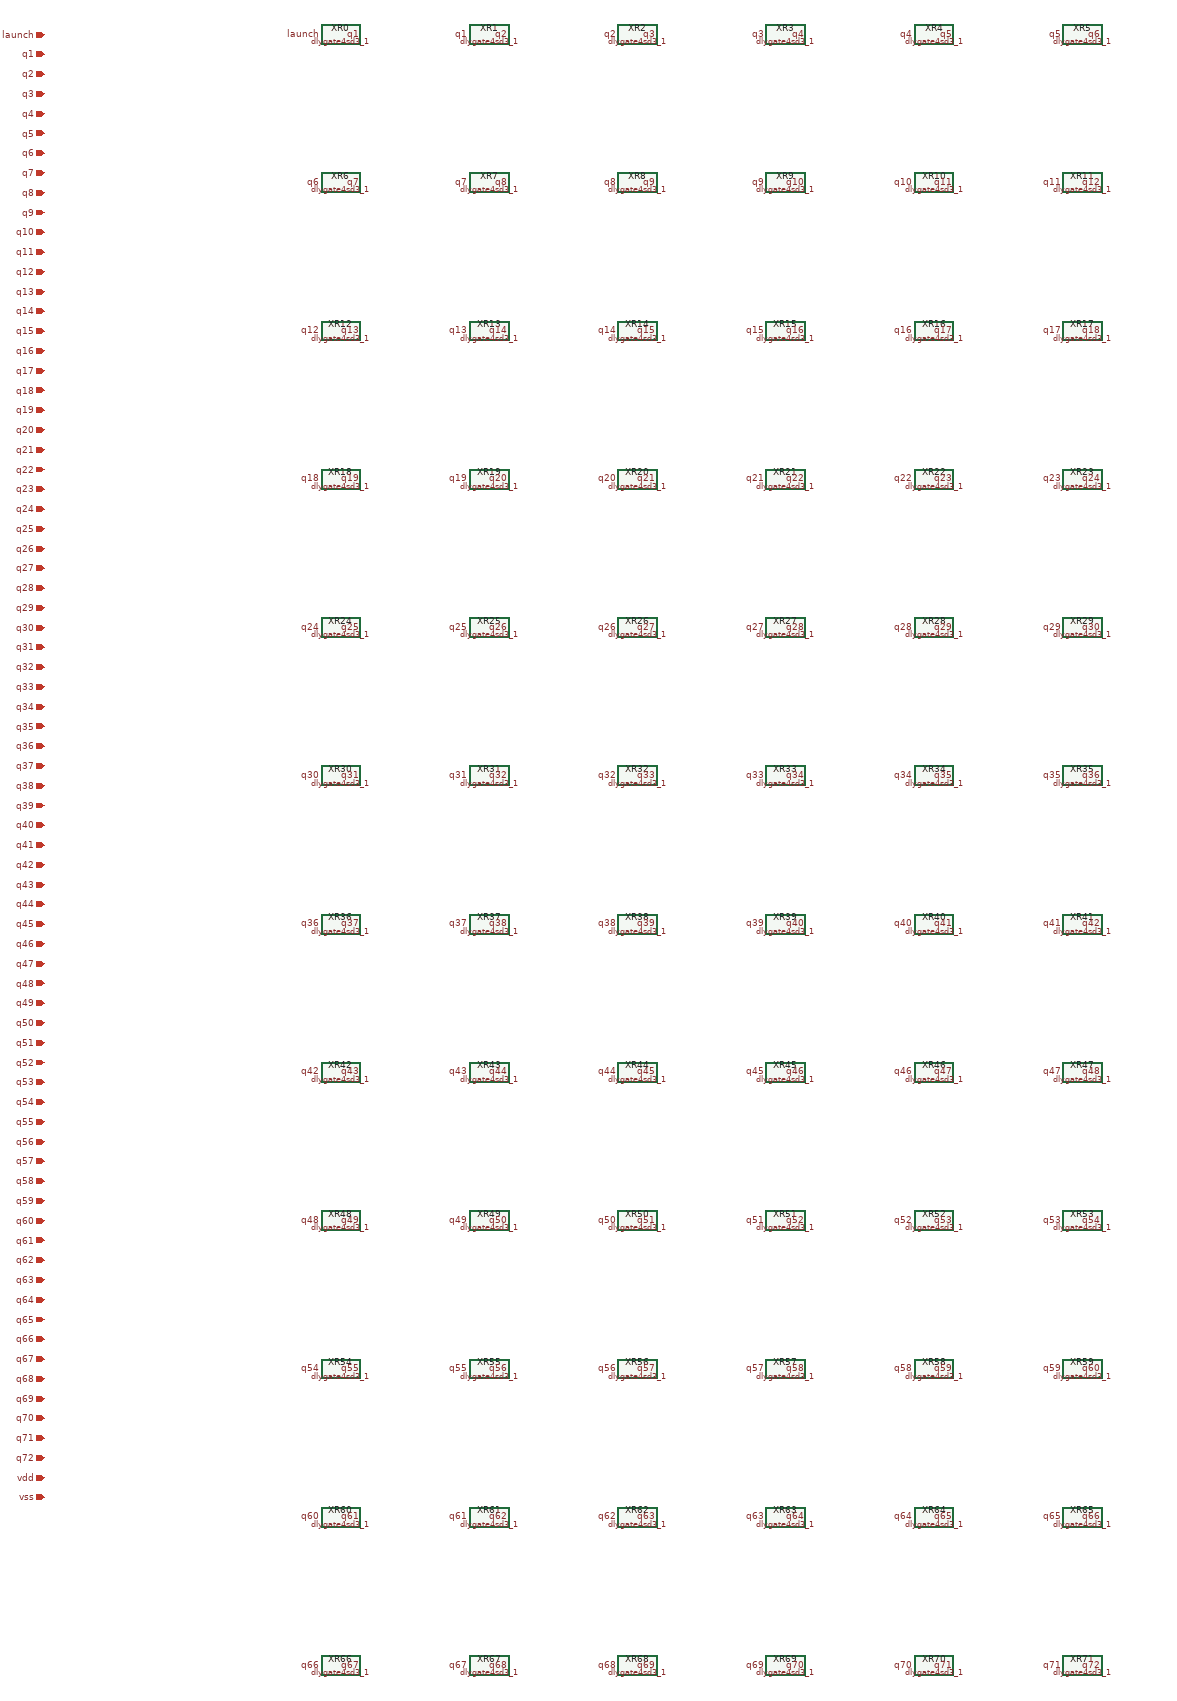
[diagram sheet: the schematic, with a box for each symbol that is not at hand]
v {xschem version=3.4.7RC file_version=1.2}
G {}
K {}
V {}
S {}
E {}

C {devices/iopin.sym} -600 0 0 0 {name=p0 lab=launch}
C {devices/iopin.sym} -600 40 0 0 {name=p1 lab=q1}
C {devices/iopin.sym} -600 80 0 0 {name=p2 lab=q2}
C {devices/iopin.sym} -600 120 0 0 {name=p3 lab=q3}
C {devices/iopin.sym} -600 160 0 0 {name=p4 lab=q4}
C {devices/iopin.sym} -600 200 0 0 {name=p5 lab=q5}
C {devices/iopin.sym} -600 240 0 0 {name=p6 lab=q6}
C {devices/iopin.sym} -600 280 0 0 {name=p7 lab=q7}
C {devices/iopin.sym} -600 320 0 0 {name=p8 lab=q8}
C {devices/iopin.sym} -600 360 0 0 {name=p9 lab=q9}
C {devices/iopin.sym} -600 400 0 0 {name=p10 lab=q10}
C {devices/iopin.sym} -600 440 0 0 {name=p11 lab=q11}
C {devices/iopin.sym} -600 480 0 0 {name=p12 lab=q12}
C {devices/iopin.sym} -600 520 0 0 {name=p13 lab=q13}
C {devices/iopin.sym} -600 560 0 0 {name=p14 lab=q14}
C {devices/iopin.sym} -600 600 0 0 {name=p15 lab=q15}
C {devices/iopin.sym} -600 640 0 0 {name=p16 lab=q16}
C {devices/iopin.sym} -600 680 0 0 {name=p17 lab=q17}
C {devices/iopin.sym} -600 720 0 0 {name=p18 lab=q18}
C {devices/iopin.sym} -600 760 0 0 {name=p19 lab=q19}
C {devices/iopin.sym} -600 800 0 0 {name=p20 lab=q20}
C {devices/iopin.sym} -600 840 0 0 {name=p21 lab=q21}
C {devices/iopin.sym} -600 880 0 0 {name=p22 lab=q22}
C {devices/iopin.sym} -600 920 0 0 {name=p23 lab=q23}
C {devices/iopin.sym} -600 960 0 0 {name=p24 lab=q24}
C {devices/iopin.sym} -600 1000 0 0 {name=p25 lab=q25}
C {devices/iopin.sym} -600 1040 0 0 {name=p26 lab=q26}
C {devices/iopin.sym} -600 1080 0 0 {name=p27 lab=q27}
C {devices/iopin.sym} -600 1120 0 0 {name=p28 lab=q28}
C {devices/iopin.sym} -600 1160 0 0 {name=p29 lab=q29}
C {devices/iopin.sym} -600 1200 0 0 {name=p30 lab=q30}
C {devices/iopin.sym} -600 1240 0 0 {name=p31 lab=q31}
C {devices/iopin.sym} -600 1280 0 0 {name=p32 lab=q32}
C {devices/iopin.sym} -600 1320 0 0 {name=p33 lab=q33}
C {devices/iopin.sym} -600 1360 0 0 {name=p34 lab=q34}
C {devices/iopin.sym} -600 1400 0 0 {name=p35 lab=q35}
C {devices/iopin.sym} -600 1440 0 0 {name=p36 lab=q36}
C {devices/iopin.sym} -600 1480 0 0 {name=p37 lab=q37}
C {devices/iopin.sym} -600 1520 0 0 {name=p38 lab=q38}
C {devices/iopin.sym} -600 1560 0 0 {name=p39 lab=q39}
C {devices/iopin.sym} -600 1600 0 0 {name=p40 lab=q40}
C {devices/iopin.sym} -600 1640 0 0 {name=p41 lab=q41}
C {devices/iopin.sym} -600 1680 0 0 {name=p42 lab=q42}
C {devices/iopin.sym} -600 1720 0 0 {name=p43 lab=q43}
C {devices/iopin.sym} -600 1760 0 0 {name=p44 lab=q44}
C {devices/iopin.sym} -600 1800 0 0 {name=p45 lab=q45}
C {devices/iopin.sym} -600 1840 0 0 {name=p46 lab=q46}
C {devices/iopin.sym} -600 1880 0 0 {name=p47 lab=q47}
C {devices/iopin.sym} -600 1920 0 0 {name=p48 lab=q48}
C {devices/iopin.sym} -600 1960 0 0 {name=p49 lab=q49}
C {devices/iopin.sym} -600 2000 0 0 {name=p50 lab=q50}
C {devices/iopin.sym} -600 2040 0 0 {name=p51 lab=q51}
C {devices/iopin.sym} -600 2080 0 0 {name=p52 lab=q52}
C {devices/iopin.sym} -600 2120 0 0 {name=p53 lab=q53}
C {devices/iopin.sym} -600 2160 0 0 {name=p54 lab=q54}
C {devices/iopin.sym} -600 2200 0 0 {name=p55 lab=q55}
C {devices/iopin.sym} -600 2240 0 0 {name=p56 lab=q56}
C {devices/iopin.sym} -600 2280 0 0 {name=p57 lab=q57}
C {devices/iopin.sym} -600 2320 0 0 {name=p58 lab=q58}
C {devices/iopin.sym} -600 2360 0 0 {name=p59 lab=q59}
C {devices/iopin.sym} -600 2400 0 0 {name=p60 lab=q60}
C {devices/iopin.sym} -600 2440 0 0 {name=p61 lab=q61}
C {devices/iopin.sym} -600 2480 0 0 {name=p62 lab=q62}
C {devices/iopin.sym} -600 2520 0 0 {name=p63 lab=q63}
C {devices/iopin.sym} -600 2560 0 0 {name=p64 lab=q64}
C {devices/iopin.sym} -600 2600 0 0 {name=p65 lab=q65}
C {devices/iopin.sym} -600 2640 0 0 {name=p66 lab=q66}
C {devices/iopin.sym} -600 2680 0 0 {name=p67 lab=q67}
C {devices/iopin.sym} -600 2720 0 0 {name=p68 lab=q68}
C {devices/iopin.sym} -600 2760 0 0 {name=p69 lab=q69}
C {devices/iopin.sym} -600 2800 0 0 {name=p70 lab=q70}
C {devices/iopin.sym} -600 2840 0 0 {name=p71 lab=q71}
C {devices/iopin.sym} -600 2880 0 0 {name=p72 lab=q72}
C {devices/iopin.sym} -600 2920 0 0 {name=p73 lab=vdd}
C {devices/iopin.sym} -600 2960 0 0 {name=p74 lab=vss}
C {sky130_stdcells/dlygate4sd3_1.sym} 0 0 0 0 {name=XR0 VGND=vss VNB=vss VPB=vdd VPWR=vdd prefix=sky130_fd_sc_hd__}
C {devices/lab_pin.sym} -40.0 0.0 0 0 {name=l0 lab=launch}
C {devices/lab_pin.sym} 40.0 0.0 0 0 {name=l1 lab=q1}
C {sky130_stdcells/dlygate4sd3_1.sym} 300 0 0 0 {name=XR1 VGND=vss VNB=vss VPB=vdd VPWR=vdd prefix=sky130_fd_sc_hd__}
C {devices/lab_pin.sym} 260.0 0.0 0 0 {name=l2 lab=q1}
C {devices/lab_pin.sym} 340.0 0.0 0 0 {name=l3 lab=q2}
C {sky130_stdcells/dlygate4sd3_1.sym} 600 0 0 0 {name=XR2 VGND=vss VNB=vss VPB=vdd VPWR=vdd prefix=sky130_fd_sc_hd__}
C {devices/lab_pin.sym} 560.0 0.0 0 0 {name=l4 lab=q2}
C {devices/lab_pin.sym} 640.0 0.0 0 0 {name=l5 lab=q3}
C {sky130_stdcells/dlygate4sd3_1.sym} 900 0 0 0 {name=XR3 VGND=vss VNB=vss VPB=vdd VPWR=vdd prefix=sky130_fd_sc_hd__}
C {devices/lab_pin.sym} 860.0 0.0 0 0 {name=l6 lab=q3}
C {devices/lab_pin.sym} 940.0 0.0 0 0 {name=l7 lab=q4}
C {sky130_stdcells/dlygate4sd3_1.sym} 1200 0 0 0 {name=XR4 VGND=vss VNB=vss VPB=vdd VPWR=vdd prefix=sky130_fd_sc_hd__}
C {devices/lab_pin.sym} 1160.0 0.0 0 0 {name=l8 lab=q4}
C {devices/lab_pin.sym} 1240.0 0.0 0 0 {name=l9 lab=q5}
C {sky130_stdcells/dlygate4sd3_1.sym} 1500 0 0 0 {name=XR5 VGND=vss VNB=vss VPB=vdd VPWR=vdd prefix=sky130_fd_sc_hd__}
C {devices/lab_pin.sym} 1460.0 0.0 0 0 {name=l10 lab=q5}
C {devices/lab_pin.sym} 1540.0 0.0 0 0 {name=l11 lab=q6}
C {sky130_stdcells/dlygate4sd3_1.sym} 0 300 0 0 {name=XR6 VGND=vss VNB=vss VPB=vdd VPWR=vdd prefix=sky130_fd_sc_hd__}
C {devices/lab_pin.sym} -40.0 300.0 0 0 {name=l12 lab=q6}
C {devices/lab_pin.sym} 40.0 300.0 0 0 {name=l13 lab=q7}
C {sky130_stdcells/dlygate4sd3_1.sym} 300 300 0 0 {name=XR7 VGND=vss VNB=vss VPB=vdd VPWR=vdd prefix=sky130_fd_sc_hd__}
C {devices/lab_pin.sym} 260.0 300.0 0 0 {name=l14 lab=q7}
C {devices/lab_pin.sym} 340.0 300.0 0 0 {name=l15 lab=q8}
C {sky130_stdcells/dlygate4sd3_1.sym} 600 300 0 0 {name=XR8 VGND=vss VNB=vss VPB=vdd VPWR=vdd prefix=sky130_fd_sc_hd__}
C {devices/lab_pin.sym} 560.0 300.0 0 0 {name=l16 lab=q8}
C {devices/lab_pin.sym} 640.0 300.0 0 0 {name=l17 lab=q9}
C {sky130_stdcells/dlygate4sd3_1.sym} 900 300 0 0 {name=XR9 VGND=vss VNB=vss VPB=vdd VPWR=vdd prefix=sky130_fd_sc_hd__}
C {devices/lab_pin.sym} 860.0 300.0 0 0 {name=l18 lab=q9}
C {devices/lab_pin.sym} 940.0 300.0 0 0 {name=l19 lab=q10}
C {sky130_stdcells/dlygate4sd3_1.sym} 1200 300 0 0 {name=XR10 VGND=vss VNB=vss VPB=vdd VPWR=vdd prefix=sky130_fd_sc_hd__}
C {devices/lab_pin.sym} 1160.0 300.0 0 0 {name=l20 lab=q10}
C {devices/lab_pin.sym} 1240.0 300.0 0 0 {name=l21 lab=q11}
C {sky130_stdcells/dlygate4sd3_1.sym} 1500 300 0 0 {name=XR11 VGND=vss VNB=vss VPB=vdd VPWR=vdd prefix=sky130_fd_sc_hd__}
C {devices/lab_pin.sym} 1460.0 300.0 0 0 {name=l22 lab=q11}
C {devices/lab_pin.sym} 1540.0 300.0 0 0 {name=l23 lab=q12}
C {sky130_stdcells/dlygate4sd3_1.sym} 0 600 0 0 {name=XR12 VGND=vss VNB=vss VPB=vdd VPWR=vdd prefix=sky130_fd_sc_hd__}
C {devices/lab_pin.sym} -40.0 600.0 0 0 {name=l24 lab=q12}
C {devices/lab_pin.sym} 40.0 600.0 0 0 {name=l25 lab=q13}
C {sky130_stdcells/dlygate4sd3_1.sym} 300 600 0 0 {name=XR13 VGND=vss VNB=vss VPB=vdd VPWR=vdd prefix=sky130_fd_sc_hd__}
C {devices/lab_pin.sym} 260.0 600.0 0 0 {name=l26 lab=q13}
C {devices/lab_pin.sym} 340.0 600.0 0 0 {name=l27 lab=q14}
C {sky130_stdcells/dlygate4sd3_1.sym} 600 600 0 0 {name=XR14 VGND=vss VNB=vss VPB=vdd VPWR=vdd prefix=sky130_fd_sc_hd__}
C {devices/lab_pin.sym} 560.0 600.0 0 0 {name=l28 lab=q14}
C {devices/lab_pin.sym} 640.0 600.0 0 0 {name=l29 lab=q15}
C {sky130_stdcells/dlygate4sd3_1.sym} 900 600 0 0 {name=XR15 VGND=vss VNB=vss VPB=vdd VPWR=vdd prefix=sky130_fd_sc_hd__}
C {devices/lab_pin.sym} 860.0 600.0 0 0 {name=l30 lab=q15}
C {devices/lab_pin.sym} 940.0 600.0 0 0 {name=l31 lab=q16}
C {sky130_stdcells/dlygate4sd3_1.sym} 1200 600 0 0 {name=XR16 VGND=vss VNB=vss VPB=vdd VPWR=vdd prefix=sky130_fd_sc_hd__}
C {devices/lab_pin.sym} 1160.0 600.0 0 0 {name=l32 lab=q16}
C {devices/lab_pin.sym} 1240.0 600.0 0 0 {name=l33 lab=q17}
C {sky130_stdcells/dlygate4sd3_1.sym} 1500 600 0 0 {name=XR17 VGND=vss VNB=vss VPB=vdd VPWR=vdd prefix=sky130_fd_sc_hd__}
C {devices/lab_pin.sym} 1460.0 600.0 0 0 {name=l34 lab=q17}
C {devices/lab_pin.sym} 1540.0 600.0 0 0 {name=l35 lab=q18}
C {sky130_stdcells/dlygate4sd3_1.sym} 0 900 0 0 {name=XR18 VGND=vss VNB=vss VPB=vdd VPWR=vdd prefix=sky130_fd_sc_hd__}
C {devices/lab_pin.sym} -40.0 900.0 0 0 {name=l36 lab=q18}
C {devices/lab_pin.sym} 40.0 900.0 0 0 {name=l37 lab=q19}
C {sky130_stdcells/dlygate4sd3_1.sym} 300 900 0 0 {name=XR19 VGND=vss VNB=vss VPB=vdd VPWR=vdd prefix=sky130_fd_sc_hd__}
C {devices/lab_pin.sym} 260.0 900.0 0 0 {name=l38 lab=q19}
C {devices/lab_pin.sym} 340.0 900.0 0 0 {name=l39 lab=q20}
C {sky130_stdcells/dlygate4sd3_1.sym} 600 900 0 0 {name=XR20 VGND=vss VNB=vss VPB=vdd VPWR=vdd prefix=sky130_fd_sc_hd__}
C {devices/lab_pin.sym} 560.0 900.0 0 0 {name=l40 lab=q20}
C {devices/lab_pin.sym} 640.0 900.0 0 0 {name=l41 lab=q21}
C {sky130_stdcells/dlygate4sd3_1.sym} 900 900 0 0 {name=XR21 VGND=vss VNB=vss VPB=vdd VPWR=vdd prefix=sky130_fd_sc_hd__}
C {devices/lab_pin.sym} 860.0 900.0 0 0 {name=l42 lab=q21}
C {devices/lab_pin.sym} 940.0 900.0 0 0 {name=l43 lab=q22}
C {sky130_stdcells/dlygate4sd3_1.sym} 1200 900 0 0 {name=XR22 VGND=vss VNB=vss VPB=vdd VPWR=vdd prefix=sky130_fd_sc_hd__}
C {devices/lab_pin.sym} 1160.0 900.0 0 0 {name=l44 lab=q22}
C {devices/lab_pin.sym} 1240.0 900.0 0 0 {name=l45 lab=q23}
C {sky130_stdcells/dlygate4sd3_1.sym} 1500 900 0 0 {name=XR23 VGND=vss VNB=vss VPB=vdd VPWR=vdd prefix=sky130_fd_sc_hd__}
C {devices/lab_pin.sym} 1460.0 900.0 0 0 {name=l46 lab=q23}
C {devices/lab_pin.sym} 1540.0 900.0 0 0 {name=l47 lab=q24}
C {sky130_stdcells/dlygate4sd3_1.sym} 0 1200 0 0 {name=XR24 VGND=vss VNB=vss VPB=vdd VPWR=vdd prefix=sky130_fd_sc_hd__}
C {devices/lab_pin.sym} -40.0 1200.0 0 0 {name=l48 lab=q24}
C {devices/lab_pin.sym} 40.0 1200.0 0 0 {name=l49 lab=q25}
C {sky130_stdcells/dlygate4sd3_1.sym} 300 1200 0 0 {name=XR25 VGND=vss VNB=vss VPB=vdd VPWR=vdd prefix=sky130_fd_sc_hd__}
C {devices/lab_pin.sym} 260.0 1200.0 0 0 {name=l50 lab=q25}
C {devices/lab_pin.sym} 340.0 1200.0 0 0 {name=l51 lab=q26}
C {sky130_stdcells/dlygate4sd3_1.sym} 600 1200 0 0 {name=XR26 VGND=vss VNB=vss VPB=vdd VPWR=vdd prefix=sky130_fd_sc_hd__}
C {devices/lab_pin.sym} 560.0 1200.0 0 0 {name=l52 lab=q26}
C {devices/lab_pin.sym} 640.0 1200.0 0 0 {name=l53 lab=q27}
C {sky130_stdcells/dlygate4sd3_1.sym} 900 1200 0 0 {name=XR27 VGND=vss VNB=vss VPB=vdd VPWR=vdd prefix=sky130_fd_sc_hd__}
C {devices/lab_pin.sym} 860.0 1200.0 0 0 {name=l54 lab=q27}
C {devices/lab_pin.sym} 940.0 1200.0 0 0 {name=l55 lab=q28}
C {sky130_stdcells/dlygate4sd3_1.sym} 1200 1200 0 0 {name=XR28 VGND=vss VNB=vss VPB=vdd VPWR=vdd prefix=sky130_fd_sc_hd__}
C {devices/lab_pin.sym} 1160.0 1200.0 0 0 {name=l56 lab=q28}
C {devices/lab_pin.sym} 1240.0 1200.0 0 0 {name=l57 lab=q29}
C {sky130_stdcells/dlygate4sd3_1.sym} 1500 1200 0 0 {name=XR29 VGND=vss VNB=vss VPB=vdd VPWR=vdd prefix=sky130_fd_sc_hd__}
C {devices/lab_pin.sym} 1460.0 1200.0 0 0 {name=l58 lab=q29}
C {devices/lab_pin.sym} 1540.0 1200.0 0 0 {name=l59 lab=q30}
C {sky130_stdcells/dlygate4sd3_1.sym} 0 1500 0 0 {name=XR30 VGND=vss VNB=vss VPB=vdd VPWR=vdd prefix=sky130_fd_sc_hd__}
C {devices/lab_pin.sym} -40.0 1500.0 0 0 {name=l60 lab=q30}
C {devices/lab_pin.sym} 40.0 1500.0 0 0 {name=l61 lab=q31}
C {sky130_stdcells/dlygate4sd3_1.sym} 300 1500 0 0 {name=XR31 VGND=vss VNB=vss VPB=vdd VPWR=vdd prefix=sky130_fd_sc_hd__}
C {devices/lab_pin.sym} 260.0 1500.0 0 0 {name=l62 lab=q31}
C {devices/lab_pin.sym} 340.0 1500.0 0 0 {name=l63 lab=q32}
C {sky130_stdcells/dlygate4sd3_1.sym} 600 1500 0 0 {name=XR32 VGND=vss VNB=vss VPB=vdd VPWR=vdd prefix=sky130_fd_sc_hd__}
C {devices/lab_pin.sym} 560.0 1500.0 0 0 {name=l64 lab=q32}
C {devices/lab_pin.sym} 640.0 1500.0 0 0 {name=l65 lab=q33}
C {sky130_stdcells/dlygate4sd3_1.sym} 900 1500 0 0 {name=XR33 VGND=vss VNB=vss VPB=vdd VPWR=vdd prefix=sky130_fd_sc_hd__}
C {devices/lab_pin.sym} 860.0 1500.0 0 0 {name=l66 lab=q33}
C {devices/lab_pin.sym} 940.0 1500.0 0 0 {name=l67 lab=q34}
C {sky130_stdcells/dlygate4sd3_1.sym} 1200 1500 0 0 {name=XR34 VGND=vss VNB=vss VPB=vdd VPWR=vdd prefix=sky130_fd_sc_hd__}
C {devices/lab_pin.sym} 1160.0 1500.0 0 0 {name=l68 lab=q34}
C {devices/lab_pin.sym} 1240.0 1500.0 0 0 {name=l69 lab=q35}
C {sky130_stdcells/dlygate4sd3_1.sym} 1500 1500 0 0 {name=XR35 VGND=vss VNB=vss VPB=vdd VPWR=vdd prefix=sky130_fd_sc_hd__}
C {devices/lab_pin.sym} 1460.0 1500.0 0 0 {name=l70 lab=q35}
C {devices/lab_pin.sym} 1540.0 1500.0 0 0 {name=l71 lab=q36}
C {sky130_stdcells/dlygate4sd3_1.sym} 0 1800 0 0 {name=XR36 VGND=vss VNB=vss VPB=vdd VPWR=vdd prefix=sky130_fd_sc_hd__}
C {devices/lab_pin.sym} -40.0 1800.0 0 0 {name=l72 lab=q36}
C {devices/lab_pin.sym} 40.0 1800.0 0 0 {name=l73 lab=q37}
C {sky130_stdcells/dlygate4sd3_1.sym} 300 1800 0 0 {name=XR37 VGND=vss VNB=vss VPB=vdd VPWR=vdd prefix=sky130_fd_sc_hd__}
C {devices/lab_pin.sym} 260.0 1800.0 0 0 {name=l74 lab=q37}
C {devices/lab_pin.sym} 340.0 1800.0 0 0 {name=l75 lab=q38}
C {sky130_stdcells/dlygate4sd3_1.sym} 600 1800 0 0 {name=XR38 VGND=vss VNB=vss VPB=vdd VPWR=vdd prefix=sky130_fd_sc_hd__}
C {devices/lab_pin.sym} 560.0 1800.0 0 0 {name=l76 lab=q38}
C {devices/lab_pin.sym} 640.0 1800.0 0 0 {name=l77 lab=q39}
C {sky130_stdcells/dlygate4sd3_1.sym} 900 1800 0 0 {name=XR39 VGND=vss VNB=vss VPB=vdd VPWR=vdd prefix=sky130_fd_sc_hd__}
C {devices/lab_pin.sym} 860.0 1800.0 0 0 {name=l78 lab=q39}
C {devices/lab_pin.sym} 940.0 1800.0 0 0 {name=l79 lab=q40}
C {sky130_stdcells/dlygate4sd3_1.sym} 1200 1800 0 0 {name=XR40 VGND=vss VNB=vss VPB=vdd VPWR=vdd prefix=sky130_fd_sc_hd__}
C {devices/lab_pin.sym} 1160.0 1800.0 0 0 {name=l80 lab=q40}
C {devices/lab_pin.sym} 1240.0 1800.0 0 0 {name=l81 lab=q41}
C {sky130_stdcells/dlygate4sd3_1.sym} 1500 1800 0 0 {name=XR41 VGND=vss VNB=vss VPB=vdd VPWR=vdd prefix=sky130_fd_sc_hd__}
C {devices/lab_pin.sym} 1460.0 1800.0 0 0 {name=l82 lab=q41}
C {devices/lab_pin.sym} 1540.0 1800.0 0 0 {name=l83 lab=q42}
C {sky130_stdcells/dlygate4sd3_1.sym} 0 2100 0 0 {name=XR42 VGND=vss VNB=vss VPB=vdd VPWR=vdd prefix=sky130_fd_sc_hd__}
C {devices/lab_pin.sym} -40.0 2100.0 0 0 {name=l84 lab=q42}
C {devices/lab_pin.sym} 40.0 2100.0 0 0 {name=l85 lab=q43}
C {sky130_stdcells/dlygate4sd3_1.sym} 300 2100 0 0 {name=XR43 VGND=vss VNB=vss VPB=vdd VPWR=vdd prefix=sky130_fd_sc_hd__}
C {devices/lab_pin.sym} 260.0 2100.0 0 0 {name=l86 lab=q43}
C {devices/lab_pin.sym} 340.0 2100.0 0 0 {name=l87 lab=q44}
C {sky130_stdcells/dlygate4sd3_1.sym} 600 2100 0 0 {name=XR44 VGND=vss VNB=vss VPB=vdd VPWR=vdd prefix=sky130_fd_sc_hd__}
C {devices/lab_pin.sym} 560.0 2100.0 0 0 {name=l88 lab=q44}
C {devices/lab_pin.sym} 640.0 2100.0 0 0 {name=l89 lab=q45}
C {sky130_stdcells/dlygate4sd3_1.sym} 900 2100 0 0 {name=XR45 VGND=vss VNB=vss VPB=vdd VPWR=vdd prefix=sky130_fd_sc_hd__}
C {devices/lab_pin.sym} 860.0 2100.0 0 0 {name=l90 lab=q45}
C {devices/lab_pin.sym} 940.0 2100.0 0 0 {name=l91 lab=q46}
C {sky130_stdcells/dlygate4sd3_1.sym} 1200 2100 0 0 {name=XR46 VGND=vss VNB=vss VPB=vdd VPWR=vdd prefix=sky130_fd_sc_hd__}
C {devices/lab_pin.sym} 1160.0 2100.0 0 0 {name=l92 lab=q46}
C {devices/lab_pin.sym} 1240.0 2100.0 0 0 {name=l93 lab=q47}
C {sky130_stdcells/dlygate4sd3_1.sym} 1500 2100 0 0 {name=XR47 VGND=vss VNB=vss VPB=vdd VPWR=vdd prefix=sky130_fd_sc_hd__}
C {devices/lab_pin.sym} 1460.0 2100.0 0 0 {name=l94 lab=q47}
C {devices/lab_pin.sym} 1540.0 2100.0 0 0 {name=l95 lab=q48}
C {sky130_stdcells/dlygate4sd3_1.sym} 0 2400 0 0 {name=XR48 VGND=vss VNB=vss VPB=vdd VPWR=vdd prefix=sky130_fd_sc_hd__}
C {devices/lab_pin.sym} -40.0 2400.0 0 0 {name=l96 lab=q48}
C {devices/lab_pin.sym} 40.0 2400.0 0 0 {name=l97 lab=q49}
C {sky130_stdcells/dlygate4sd3_1.sym} 300 2400 0 0 {name=XR49 VGND=vss VNB=vss VPB=vdd VPWR=vdd prefix=sky130_fd_sc_hd__}
C {devices/lab_pin.sym} 260.0 2400.0 0 0 {name=l98 lab=q49}
C {devices/lab_pin.sym} 340.0 2400.0 0 0 {name=l99 lab=q50}
C {sky130_stdcells/dlygate4sd3_1.sym} 600 2400 0 0 {name=XR50 VGND=vss VNB=vss VPB=vdd VPWR=vdd prefix=sky130_fd_sc_hd__}
C {devices/lab_pin.sym} 560.0 2400.0 0 0 {name=l100 lab=q50}
C {devices/lab_pin.sym} 640.0 2400.0 0 0 {name=l101 lab=q51}
C {sky130_stdcells/dlygate4sd3_1.sym} 900 2400 0 0 {name=XR51 VGND=vss VNB=vss VPB=vdd VPWR=vdd prefix=sky130_fd_sc_hd__}
C {devices/lab_pin.sym} 860.0 2400.0 0 0 {name=l102 lab=q51}
C {devices/lab_pin.sym} 940.0 2400.0 0 0 {name=l103 lab=q52}
C {sky130_stdcells/dlygate4sd3_1.sym} 1200 2400 0 0 {name=XR52 VGND=vss VNB=vss VPB=vdd VPWR=vdd prefix=sky130_fd_sc_hd__}
C {devices/lab_pin.sym} 1160.0 2400.0 0 0 {name=l104 lab=q52}
C {devices/lab_pin.sym} 1240.0 2400.0 0 0 {name=l105 lab=q53}
C {sky130_stdcells/dlygate4sd3_1.sym} 1500 2400 0 0 {name=XR53 VGND=vss VNB=vss VPB=vdd VPWR=vdd prefix=sky130_fd_sc_hd__}
C {devices/lab_pin.sym} 1460.0 2400.0 0 0 {name=l106 lab=q53}
C {devices/lab_pin.sym} 1540.0 2400.0 0 0 {name=l107 lab=q54}
C {sky130_stdcells/dlygate4sd3_1.sym} 0 2700 0 0 {name=XR54 VGND=vss VNB=vss VPB=vdd VPWR=vdd prefix=sky130_fd_sc_hd__}
C {devices/lab_pin.sym} -40.0 2700.0 0 0 {name=l108 lab=q54}
C {devices/lab_pin.sym} 40.0 2700.0 0 0 {name=l109 lab=q55}
C {sky130_stdcells/dlygate4sd3_1.sym} 300 2700 0 0 {name=XR55 VGND=vss VNB=vss VPB=vdd VPWR=vdd prefix=sky130_fd_sc_hd__}
C {devices/lab_pin.sym} 260.0 2700.0 0 0 {name=l110 lab=q55}
C {devices/lab_pin.sym} 340.0 2700.0 0 0 {name=l111 lab=q56}
C {sky130_stdcells/dlygate4sd3_1.sym} 600 2700 0 0 {name=XR56 VGND=vss VNB=vss VPB=vdd VPWR=vdd prefix=sky130_fd_sc_hd__}
C {devices/lab_pin.sym} 560.0 2700.0 0 0 {name=l112 lab=q56}
C {devices/lab_pin.sym} 640.0 2700.0 0 0 {name=l113 lab=q57}
C {sky130_stdcells/dlygate4sd3_1.sym} 900 2700 0 0 {name=XR57 VGND=vss VNB=vss VPB=vdd VPWR=vdd prefix=sky130_fd_sc_hd__}
C {devices/lab_pin.sym} 860.0 2700.0 0 0 {name=l114 lab=q57}
C {devices/lab_pin.sym} 940.0 2700.0 0 0 {name=l115 lab=q58}
C {sky130_stdcells/dlygate4sd3_1.sym} 1200 2700 0 0 {name=XR58 VGND=vss VNB=vss VPB=vdd VPWR=vdd prefix=sky130_fd_sc_hd__}
C {devices/lab_pin.sym} 1160.0 2700.0 0 0 {name=l116 lab=q58}
C {devices/lab_pin.sym} 1240.0 2700.0 0 0 {name=l117 lab=q59}
C {sky130_stdcells/dlygate4sd3_1.sym} 1500 2700 0 0 {name=XR59 VGND=vss VNB=vss VPB=vdd VPWR=vdd prefix=sky130_fd_sc_hd__}
C {devices/lab_pin.sym} 1460.0 2700.0 0 0 {name=l118 lab=q59}
C {devices/lab_pin.sym} 1540.0 2700.0 0 0 {name=l119 lab=q60}
C {sky130_stdcells/dlygate4sd3_1.sym} 0 3000 0 0 {name=XR60 VGND=vss VNB=vss VPB=vdd VPWR=vdd prefix=sky130_fd_sc_hd__}
C {devices/lab_pin.sym} -40.0 3000.0 0 0 {name=l120 lab=q60}
C {devices/lab_pin.sym} 40.0 3000.0 0 0 {name=l121 lab=q61}
C {sky130_stdcells/dlygate4sd3_1.sym} 300 3000 0 0 {name=XR61 VGND=vss VNB=vss VPB=vdd VPWR=vdd prefix=sky130_fd_sc_hd__}
C {devices/lab_pin.sym} 260.0 3000.0 0 0 {name=l122 lab=q61}
C {devices/lab_pin.sym} 340.0 3000.0 0 0 {name=l123 lab=q62}
C {sky130_stdcells/dlygate4sd3_1.sym} 600 3000 0 0 {name=XR62 VGND=vss VNB=vss VPB=vdd VPWR=vdd prefix=sky130_fd_sc_hd__}
C {devices/lab_pin.sym} 560.0 3000.0 0 0 {name=l124 lab=q62}
C {devices/lab_pin.sym} 640.0 3000.0 0 0 {name=l125 lab=q63}
C {sky130_stdcells/dlygate4sd3_1.sym} 900 3000 0 0 {name=XR63 VGND=vss VNB=vss VPB=vdd VPWR=vdd prefix=sky130_fd_sc_hd__}
C {devices/lab_pin.sym} 860.0 3000.0 0 0 {name=l126 lab=q63}
C {devices/lab_pin.sym} 940.0 3000.0 0 0 {name=l127 lab=q64}
C {sky130_stdcells/dlygate4sd3_1.sym} 1200 3000 0 0 {name=XR64 VGND=vss VNB=vss VPB=vdd VPWR=vdd prefix=sky130_fd_sc_hd__}
C {devices/lab_pin.sym} 1160.0 3000.0 0 0 {name=l128 lab=q64}
C {devices/lab_pin.sym} 1240.0 3000.0 0 0 {name=l129 lab=q65}
C {sky130_stdcells/dlygate4sd3_1.sym} 1500 3000 0 0 {name=XR65 VGND=vss VNB=vss VPB=vdd VPWR=vdd prefix=sky130_fd_sc_hd__}
C {devices/lab_pin.sym} 1460.0 3000.0 0 0 {name=l130 lab=q65}
C {devices/lab_pin.sym} 1540.0 3000.0 0 0 {name=l131 lab=q66}
C {sky130_stdcells/dlygate4sd3_1.sym} 0 3300 0 0 {name=XR66 VGND=vss VNB=vss VPB=vdd VPWR=vdd prefix=sky130_fd_sc_hd__}
C {devices/lab_pin.sym} -40.0 3300.0 0 0 {name=l132 lab=q66}
C {devices/lab_pin.sym} 40.0 3300.0 0 0 {name=l133 lab=q67}
C {sky130_stdcells/dlygate4sd3_1.sym} 300 3300 0 0 {name=XR67 VGND=vss VNB=vss VPB=vdd VPWR=vdd prefix=sky130_fd_sc_hd__}
C {devices/lab_pin.sym} 260.0 3300.0 0 0 {name=l134 lab=q67}
C {devices/lab_pin.sym} 340.0 3300.0 0 0 {name=l135 lab=q68}
C {sky130_stdcells/dlygate4sd3_1.sym} 600 3300 0 0 {name=XR68 VGND=vss VNB=vss VPB=vdd VPWR=vdd prefix=sky130_fd_sc_hd__}
C {devices/lab_pin.sym} 560.0 3300.0 0 0 {name=l136 lab=q68}
C {devices/lab_pin.sym} 640.0 3300.0 0 0 {name=l137 lab=q69}
C {sky130_stdcells/dlygate4sd3_1.sym} 900 3300 0 0 {name=XR69 VGND=vss VNB=vss VPB=vdd VPWR=vdd prefix=sky130_fd_sc_hd__}
C {devices/lab_pin.sym} 860.0 3300.0 0 0 {name=l138 lab=q69}
C {devices/lab_pin.sym} 940.0 3300.0 0 0 {name=l139 lab=q70}
C {sky130_stdcells/dlygate4sd3_1.sym} 1200 3300 0 0 {name=XR70 VGND=vss VNB=vss VPB=vdd VPWR=vdd prefix=sky130_fd_sc_hd__}
C {devices/lab_pin.sym} 1160.0 3300.0 0 0 {name=l140 lab=q70}
C {devices/lab_pin.sym} 1240.0 3300.0 0 0 {name=l141 lab=q71}
C {sky130_stdcells/dlygate4sd3_1.sym} 1500 3300 0 0 {name=XR71 VGND=vss VNB=vss VPB=vdd VPWR=vdd prefix=sky130_fd_sc_hd__}
C {devices/lab_pin.sym} 1460.0 3300.0 0 0 {name=l142 lab=q71}
C {devices/lab_pin.sym} 1540.0 3300.0 0 0 {name=l143 lab=q72}
